VERSION 5.8 ;
BUSBITCHARS "[]" ;
DIVIDERCHAR "/" ;
UNITS
    DATABASE MICRONS 1000 ;
END UNITS

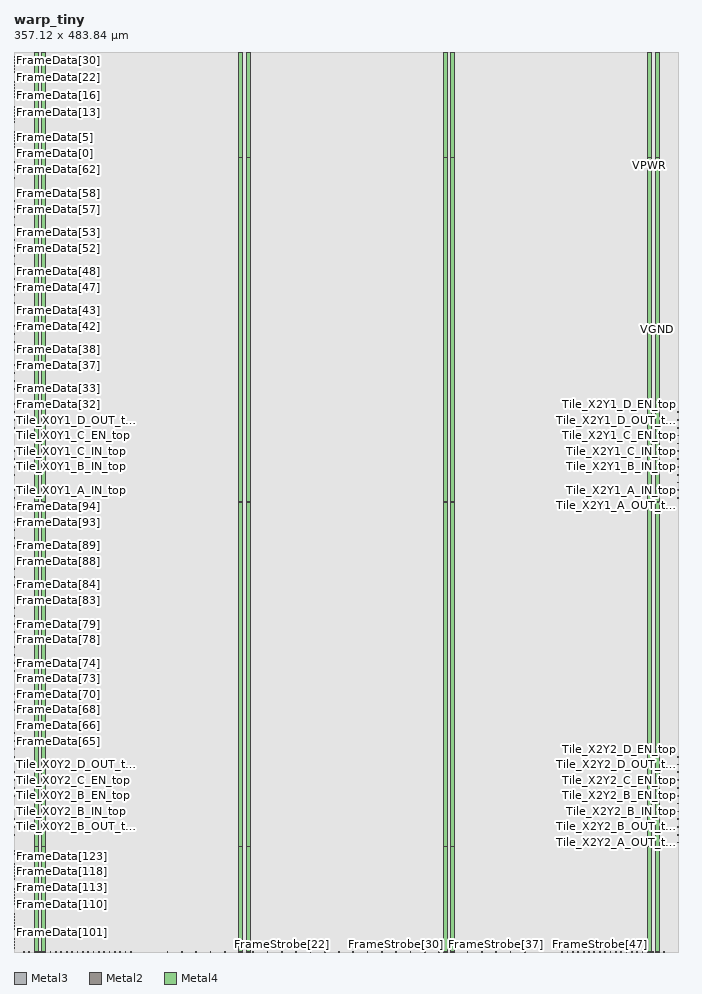
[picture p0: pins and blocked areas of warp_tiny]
MACRO warp_tiny
  FOREIGN warp_tiny 0 0 ;
  CLASS BLOCK ;
  SIZE 357.12 BY 483.84 ;
  PIN FrameData[0]
    DIRECTION INPUT ;
    USE SIGNAL ;
    PORT
      LAYER Metal3 ;
        RECT  0 429.04 0.4 429.44 ;
    END
  END FrameData[0]
  PIN FrameData[100]
    DIRECTION INPUT ;
    USE SIGNAL ;
    PORT
      LAYER Metal3 ;
        RECT  0 8.62 0.4 9.02 ;
    END
  END FrameData[100]
  PIN FrameData[101]
    DIRECTION INPUT ;
    USE SIGNAL ;
    PORT
      LAYER Metal3 ;
        RECT  0 10.3 0.4 10.7 ;
    END
  END FrameData[101]
  PIN FrameData[102]
    DIRECTION INPUT ;
    USE SIGNAL ;
    PORT
      LAYER Metal3 ;
        RECT  0 11.98 0.4 12.38 ;
    END
  END FrameData[102]
  PIN FrameData[103]
    DIRECTION INPUT ;
    USE SIGNAL ;
    PORT
      LAYER Metal3 ;
        RECT  0 13.66 0.4 14.06 ;
    END
  END FrameData[103]
  PIN FrameData[104]
    DIRECTION INPUT ;
    USE SIGNAL ;
    PORT
      LAYER Metal3 ;
        RECT  0 15.34 0.4 15.74 ;
    END
  END FrameData[104]
  PIN FrameData[105]
    DIRECTION INPUT ;
    USE SIGNAL ;
    PORT
      LAYER Metal3 ;
        RECT  0 17.02 0.4 17.42 ;
    END
  END FrameData[105]
  PIN FrameData[106]
    DIRECTION INPUT ;
    USE SIGNAL ;
    PORT
      LAYER Metal3 ;
        RECT  0 18.7 0.4 19.1 ;
    END
  END FrameData[106]
  PIN FrameData[107]
    DIRECTION INPUT ;
    USE SIGNAL ;
    PORT
      LAYER Metal3 ;
        RECT  0 20.38 0.4 20.78 ;
    END
  END FrameData[107]
  PIN FrameData[108]
    DIRECTION INPUT ;
    USE SIGNAL ;
    PORT
      LAYER Metal3 ;
        RECT  0 22.06 0.4 22.46 ;
    END
  END FrameData[108]
  PIN FrameData[109]
    DIRECTION INPUT ;
    USE SIGNAL ;
    PORT
      LAYER Metal3 ;
        RECT  0 23.74 0.4 24.14 ;
    END
  END FrameData[109]
  PIN FrameData[10]
    DIRECTION INPUT ;
    USE SIGNAL ;
    PORT
      LAYER Metal3 ;
        RECT  0 445.84 0.4 446.24 ;
    END
  END FrameData[10]
  PIN FrameData[110]
    DIRECTION INPUT ;
    USE SIGNAL ;
    PORT
      LAYER Metal3 ;
        RECT  0 25.42 0.4 25.82 ;
    END
  END FrameData[110]
  PIN FrameData[111]
    DIRECTION INPUT ;
    USE SIGNAL ;
    PORT
      LAYER Metal3 ;
        RECT  0 27.1 0.4 27.5 ;
    END
  END FrameData[111]
  PIN FrameData[112]
    DIRECTION INPUT ;
    USE SIGNAL ;
    PORT
      LAYER Metal3 ;
        RECT  0 28.78 0.4 29.18 ;
    END
  END FrameData[112]
  PIN FrameData[113]
    DIRECTION INPUT ;
    USE SIGNAL ;
    PORT
      LAYER Metal3 ;
        RECT  0 30.46 0.4 30.86 ;
    END
  END FrameData[113]
  PIN FrameData[114]
    DIRECTION INPUT ;
    USE SIGNAL ;
    PORT
      LAYER Metal3 ;
        RECT  0 32.14 0.4 32.54 ;
    END
  END FrameData[114]
  PIN FrameData[115]
    DIRECTION INPUT ;
    USE SIGNAL ;
    PORT
      LAYER Metal3 ;
        RECT  0 33.82 0.4 34.22 ;
    END
  END FrameData[115]
  PIN FrameData[116]
    DIRECTION INPUT ;
    USE SIGNAL ;
    PORT
      LAYER Metal3 ;
        RECT  0 35.5 0.4 35.9 ;
    END
  END FrameData[116]
  PIN FrameData[117]
    DIRECTION INPUT ;
    USE SIGNAL ;
    PORT
      LAYER Metal3 ;
        RECT  0 37.18 0.4 37.58 ;
    END
  END FrameData[117]
  PIN FrameData[118]
    DIRECTION INPUT ;
    USE SIGNAL ;
    PORT
      LAYER Metal3 ;
        RECT  0 38.86 0.4 39.26 ;
    END
  END FrameData[118]
  PIN FrameData[119]
    DIRECTION INPUT ;
    USE SIGNAL ;
    PORT
      LAYER Metal3 ;
        RECT  0 40.54 0.4 40.94 ;
    END
  END FrameData[119]
  PIN FrameData[11]
    DIRECTION INPUT ;
    USE SIGNAL ;
    PORT
      LAYER Metal3 ;
        RECT  0 447.52 0.4 447.92 ;
    END
  END FrameData[11]
  PIN FrameData[120]
    DIRECTION INPUT ;
    USE SIGNAL ;
    PORT
      LAYER Metal3 ;
        RECT  0 42.22 0.4 42.62 ;
    END
  END FrameData[120]
  PIN FrameData[121]
    DIRECTION INPUT ;
    USE SIGNAL ;
    PORT
      LAYER Metal3 ;
        RECT  0 43.9 0.4 44.3 ;
    END
  END FrameData[121]
  PIN FrameData[122]
    DIRECTION INPUT ;
    USE SIGNAL ;
    PORT
      LAYER Metal3 ;
        RECT  0 45.58 0.4 45.98 ;
    END
  END FrameData[122]
  PIN FrameData[123]
    DIRECTION INPUT ;
    USE SIGNAL ;
    PORT
      LAYER Metal3 ;
        RECT  0 47.26 0.4 47.66 ;
    END
  END FrameData[123]
  PIN FrameData[124]
    DIRECTION INPUT ;
    USE SIGNAL ;
    PORT
      LAYER Metal3 ;
        RECT  0 48.94 0.4 49.34 ;
    END
  END FrameData[124]
  PIN FrameData[125]
    DIRECTION INPUT ;
    USE SIGNAL ;
    PORT
      LAYER Metal3 ;
        RECT  0 50.62 0.4 51.02 ;
    END
  END FrameData[125]
  PIN FrameData[126]
    DIRECTION INPUT ;
    USE SIGNAL ;
    PORT
      LAYER Metal3 ;
        RECT  0 52.3 0.4 52.7 ;
    END
  END FrameData[126]
  PIN FrameData[127]
    DIRECTION INPUT ;
    USE SIGNAL ;
    PORT
      LAYER Metal3 ;
        RECT  0 53.98 0.4 54.38 ;
    END
  END FrameData[127]
  PIN FrameData[12]
    DIRECTION INPUT ;
    USE SIGNAL ;
    PORT
      LAYER Metal3 ;
        RECT  0 449.2 0.4 449.6 ;
    END
  END FrameData[12]
  PIN FrameData[13]
    DIRECTION INPUT ;
    USE SIGNAL ;
    PORT
      LAYER Metal3 ;
        RECT  0 450.88 0.4 451.28 ;
    END
  END FrameData[13]
  PIN FrameData[14]
    DIRECTION INPUT ;
    USE SIGNAL ;
    PORT
      LAYER Metal3 ;
        RECT  0 452.56 0.4 452.96 ;
    END
  END FrameData[14]
  PIN FrameData[15]
    DIRECTION INPUT ;
    USE SIGNAL ;
    PORT
      LAYER Metal3 ;
        RECT  0 454.24 0.4 454.64 ;
    END
  END FrameData[15]
  PIN FrameData[16]
    DIRECTION INPUT ;
    USE SIGNAL ;
    PORT
      LAYER Metal3 ;
        RECT  0 455.92 0.4 456.32 ;
    END
  END FrameData[16]
  PIN FrameData[17]
    DIRECTION INPUT ;
    USE SIGNAL ;
    PORT
      LAYER Metal3 ;
        RECT  0 457.6 0.4 458 ;
    END
  END FrameData[17]
  PIN FrameData[18]
    DIRECTION INPUT ;
    USE SIGNAL ;
    PORT
      LAYER Metal3 ;
        RECT  0 459.28 0.4 459.68 ;
    END
  END FrameData[18]
  PIN FrameData[19]
    DIRECTION INPUT ;
    USE SIGNAL ;
    PORT
      LAYER Metal3 ;
        RECT  0 460.96 0.4 461.36 ;
    END
  END FrameData[19]
  PIN FrameData[1]
    DIRECTION INPUT ;
    USE SIGNAL ;
    PORT
      LAYER Metal3 ;
        RECT  0 430.72 0.4 431.12 ;
    END
  END FrameData[1]
  PIN FrameData[20]
    DIRECTION INPUT ;
    USE SIGNAL ;
    PORT
      LAYER Metal3 ;
        RECT  0 462.64 0.4 463.04 ;
    END
  END FrameData[20]
  PIN FrameData[21]
    DIRECTION INPUT ;
    USE SIGNAL ;
    PORT
      LAYER Metal3 ;
        RECT  0 464.32 0.4 464.72 ;
    END
  END FrameData[21]
  PIN FrameData[22]
    DIRECTION INPUT ;
    USE SIGNAL ;
    PORT
      LAYER Metal3 ;
        RECT  0 466 0.4 466.4 ;
    END
  END FrameData[22]
  PIN FrameData[23]
    DIRECTION INPUT ;
    USE SIGNAL ;
    PORT
      LAYER Metal3 ;
        RECT  0 467.68 0.4 468.08 ;
    END
  END FrameData[23]
  PIN FrameData[24]
    DIRECTION INPUT ;
    USE SIGNAL ;
    PORT
      LAYER Metal3 ;
        RECT  0 469.36 0.4 469.76 ;
    END
  END FrameData[24]
  PIN FrameData[25]
    DIRECTION INPUT ;
    USE SIGNAL ;
    PORT
      LAYER Metal3 ;
        RECT  0 471.04 0.4 471.44 ;
    END
  END FrameData[25]
  PIN FrameData[26]
    DIRECTION INPUT ;
    USE SIGNAL ;
    PORT
      LAYER Metal3 ;
        RECT  0 472.72 0.4 473.12 ;
    END
  END FrameData[26]
  PIN FrameData[27]
    DIRECTION INPUT ;
    USE SIGNAL ;
    PORT
      LAYER Metal3 ;
        RECT  0 474.4 0.4 474.8 ;
    END
  END FrameData[27]
  PIN FrameData[28]
    DIRECTION INPUT ;
    USE SIGNAL ;
    PORT
      LAYER Metal3 ;
        RECT  0 476.08 0.4 476.48 ;
    END
  END FrameData[28]
  PIN FrameData[29]
    DIRECTION INPUT ;
    USE SIGNAL ;
    PORT
      LAYER Metal3 ;
        RECT  0 477.76 0.4 478.16 ;
    END
  END FrameData[29]
  PIN FrameData[2]
    DIRECTION INPUT ;
    USE SIGNAL ;
    PORT
      LAYER Metal3 ;
        RECT  0 432.4 0.4 432.8 ;
    END
  END FrameData[2]
  PIN FrameData[30]
    DIRECTION INPUT ;
    USE SIGNAL ;
    PORT
      LAYER Metal3 ;
        RECT  0 479.44 0.4 479.84 ;
    END
  END FrameData[30]
  PIN FrameData[31]
    DIRECTION INPUT ;
    USE SIGNAL ;
    PORT
      LAYER Metal3 ;
        RECT  0 481.12 0.4 481.52 ;
    END
  END FrameData[31]
  PIN FrameData[32]
    DIRECTION INPUT ;
    USE SIGNAL ;
    PORT
      LAYER Metal3 ;
        RECT  0 294.22 0.4 294.62 ;
    END
  END FrameData[32]
  PIN FrameData[33]
    DIRECTION INPUT ;
    USE SIGNAL ;
    PORT
      LAYER Metal3 ;
        RECT  0 298.42 0.4 298.82 ;
    END
  END FrameData[33]
  PIN FrameData[34]
    DIRECTION INPUT ;
    USE SIGNAL ;
    PORT
      LAYER Metal3 ;
        RECT  0 302.62 0.4 303.02 ;
    END
  END FrameData[34]
  PIN FrameData[35]
    DIRECTION INPUT ;
    USE SIGNAL ;
    PORT
      LAYER Metal3 ;
        RECT  0 306.82 0.4 307.22 ;
    END
  END FrameData[35]
  PIN FrameData[36]
    DIRECTION INPUT ;
    USE SIGNAL ;
    PORT
      LAYER Metal3 ;
        RECT  0 311.02 0.4 311.42 ;
    END
  END FrameData[36]
  PIN FrameData[37]
    DIRECTION INPUT ;
    USE SIGNAL ;
    PORT
      LAYER Metal3 ;
        RECT  0 315.22 0.4 315.62 ;
    END
  END FrameData[37]
  PIN FrameData[38]
    DIRECTION INPUT ;
    USE SIGNAL ;
    PORT
      LAYER Metal3 ;
        RECT  0 319.42 0.4 319.82 ;
    END
  END FrameData[38]
  PIN FrameData[39]
    DIRECTION INPUT ;
    USE SIGNAL ;
    PORT
      LAYER Metal3 ;
        RECT  0 323.62 0.4 324.02 ;
    END
  END FrameData[39]
  PIN FrameData[3]
    DIRECTION INPUT ;
    USE SIGNAL ;
    PORT
      LAYER Metal3 ;
        RECT  0 434.08 0.4 434.48 ;
    END
  END FrameData[3]
  PIN FrameData[40]
    DIRECTION INPUT ;
    USE SIGNAL ;
    PORT
      LAYER Metal3 ;
        RECT  0 327.82 0.4 328.22 ;
    END
  END FrameData[40]
  PIN FrameData[41]
    DIRECTION INPUT ;
    USE SIGNAL ;
    PORT
      LAYER Metal3 ;
        RECT  0 332.02 0.4 332.42 ;
    END
  END FrameData[41]
  PIN FrameData[42]
    DIRECTION INPUT ;
    USE SIGNAL ;
    PORT
      LAYER Metal3 ;
        RECT  0 336.22 0.4 336.62 ;
    END
  END FrameData[42]
  PIN FrameData[43]
    DIRECTION INPUT ;
    USE SIGNAL ;
    PORT
      LAYER Metal3 ;
        RECT  0 340.42 0.4 340.82 ;
    END
  END FrameData[43]
  PIN FrameData[44]
    DIRECTION INPUT ;
    USE SIGNAL ;
    PORT
      LAYER Metal3 ;
        RECT  0 344.62 0.4 345.02 ;
    END
  END FrameData[44]
  PIN FrameData[45]
    DIRECTION INPUT ;
    USE SIGNAL ;
    PORT
      LAYER Metal3 ;
        RECT  0 348.82 0.4 349.22 ;
    END
  END FrameData[45]
  PIN FrameData[46]
    DIRECTION INPUT ;
    USE SIGNAL ;
    PORT
      LAYER Metal3 ;
        RECT  0 353.02 0.4 353.42 ;
    END
  END FrameData[46]
  PIN FrameData[47]
    DIRECTION INPUT ;
    USE SIGNAL ;
    PORT
      LAYER Metal3 ;
        RECT  0 357.22 0.4 357.62 ;
    END
  END FrameData[47]
  PIN FrameData[48]
    DIRECTION INPUT ;
    USE SIGNAL ;
    PORT
      LAYER Metal3 ;
        RECT  0 361.42 0.4 361.82 ;
    END
  END FrameData[48]
  PIN FrameData[49]
    DIRECTION INPUT ;
    USE SIGNAL ;
    PORT
      LAYER Metal3 ;
        RECT  0 365.62 0.4 366.02 ;
    END
  END FrameData[49]
  PIN FrameData[4]
    DIRECTION INPUT ;
    USE SIGNAL ;
    PORT
      LAYER Metal3 ;
        RECT  0 435.76 0.4 436.16 ;
    END
  END FrameData[4]
  PIN FrameData[50]
    DIRECTION INPUT ;
    USE SIGNAL ;
    PORT
      LAYER Metal3 ;
        RECT  0 369.82 0.4 370.22 ;
    END
  END FrameData[50]
  PIN FrameData[51]
    DIRECTION INPUT ;
    USE SIGNAL ;
    PORT
      LAYER Metal3 ;
        RECT  0 374.02 0.4 374.42 ;
    END
  END FrameData[51]
  PIN FrameData[52]
    DIRECTION INPUT ;
    USE SIGNAL ;
    PORT
      LAYER Metal3 ;
        RECT  0 378.22 0.4 378.62 ;
    END
  END FrameData[52]
  PIN FrameData[53]
    DIRECTION INPUT ;
    USE SIGNAL ;
    PORT
      LAYER Metal3 ;
        RECT  0 382.42 0.4 382.82 ;
    END
  END FrameData[53]
  PIN FrameData[54]
    DIRECTION INPUT ;
    USE SIGNAL ;
    PORT
      LAYER Metal3 ;
        RECT  0 386.62 0.4 387.02 ;
    END
  END FrameData[54]
  PIN FrameData[55]
    DIRECTION INPUT ;
    USE SIGNAL ;
    PORT
      LAYER Metal3 ;
        RECT  0 390.82 0.4 391.22 ;
    END
  END FrameData[55]
  PIN FrameData[56]
    DIRECTION INPUT ;
    USE SIGNAL ;
    PORT
      LAYER Metal3 ;
        RECT  0 395.02 0.4 395.42 ;
    END
  END FrameData[56]
  PIN FrameData[57]
    DIRECTION INPUT ;
    USE SIGNAL ;
    PORT
      LAYER Metal3 ;
        RECT  0 399.22 0.4 399.62 ;
    END
  END FrameData[57]
  PIN FrameData[58]
    DIRECTION INPUT ;
    USE SIGNAL ;
    PORT
      LAYER Metal3 ;
        RECT  0 403.42 0.4 403.82 ;
    END
  END FrameData[58]
  PIN FrameData[59]
    DIRECTION INPUT ;
    USE SIGNAL ;
    PORT
      LAYER Metal3 ;
        RECT  0 407.62 0.4 408.02 ;
    END
  END FrameData[59]
  PIN FrameData[5]
    DIRECTION INPUT ;
    USE SIGNAL ;
    PORT
      LAYER Metal3 ;
        RECT  0 437.44 0.4 437.84 ;
    END
  END FrameData[5]
  PIN FrameData[60]
    DIRECTION INPUT ;
    USE SIGNAL ;
    PORT
      LAYER Metal3 ;
        RECT  0 411.82 0.4 412.22 ;
    END
  END FrameData[60]
  PIN FrameData[61]
    DIRECTION INPUT ;
    USE SIGNAL ;
    PORT
      LAYER Metal3 ;
        RECT  0 416.02 0.4 416.42 ;
    END
  END FrameData[61]
  PIN FrameData[62]
    DIRECTION INPUT ;
    USE SIGNAL ;
    PORT
      LAYER Metal3 ;
        RECT  0 420.22 0.4 420.62 ;
    END
  END FrameData[62]
  PIN FrameData[63]
    DIRECTION INPUT ;
    USE SIGNAL ;
    PORT
      LAYER Metal3 ;
        RECT  0 424.42 0.4 424.82 ;
    END
  END FrameData[63]
  PIN FrameData[64]
    DIRECTION INPUT ;
    USE SIGNAL ;
    PORT
      LAYER Metal3 ;
        RECT  0 109 0.4 109.4 ;
    END
  END FrameData[64]
  PIN FrameData[65]
    DIRECTION INPUT ;
    USE SIGNAL ;
    PORT
      LAYER Metal3 ;
        RECT  0 113.2 0.4 113.6 ;
    END
  END FrameData[65]
  PIN FrameData[66]
    DIRECTION INPUT ;
    USE SIGNAL ;
    PORT
      LAYER Metal3 ;
        RECT  0 117.4 0.4 117.8 ;
    END
  END FrameData[66]
  PIN FrameData[67]
    DIRECTION INPUT ;
    USE SIGNAL ;
    PORT
      LAYER Metal3 ;
        RECT  0 121.6 0.4 122 ;
    END
  END FrameData[67]
  PIN FrameData[68]
    DIRECTION INPUT ;
    USE SIGNAL ;
    PORT
      LAYER Metal3 ;
        RECT  0 125.8 0.4 126.2 ;
    END
  END FrameData[68]
  PIN FrameData[69]
    DIRECTION INPUT ;
    USE SIGNAL ;
    PORT
      LAYER Metal3 ;
        RECT  0 130 0.4 130.4 ;
    END
  END FrameData[69]
  PIN FrameData[6]
    DIRECTION INPUT ;
    USE SIGNAL ;
    PORT
      LAYER Metal3 ;
        RECT  0 439.12 0.4 439.52 ;
    END
  END FrameData[6]
  PIN FrameData[70]
    DIRECTION INPUT ;
    USE SIGNAL ;
    PORT
      LAYER Metal3 ;
        RECT  0 134.2 0.4 134.6 ;
    END
  END FrameData[70]
  PIN FrameData[71]
    DIRECTION INPUT ;
    USE SIGNAL ;
    PORT
      LAYER Metal3 ;
        RECT  0 138.4 0.4 138.8 ;
    END
  END FrameData[71]
  PIN FrameData[72]
    DIRECTION INPUT ;
    USE SIGNAL ;
    PORT
      LAYER Metal3 ;
        RECT  0 142.6 0.4 143 ;
    END
  END FrameData[72]
  PIN FrameData[73]
    DIRECTION INPUT ;
    USE SIGNAL ;
    PORT
      LAYER Metal3 ;
        RECT  0 146.8 0.4 147.2 ;
    END
  END FrameData[73]
  PIN FrameData[74]
    DIRECTION INPUT ;
    USE SIGNAL ;
    PORT
      LAYER Metal3 ;
        RECT  0 151 0.4 151.4 ;
    END
  END FrameData[74]
  PIN FrameData[75]
    DIRECTION INPUT ;
    USE SIGNAL ;
    PORT
      LAYER Metal3 ;
        RECT  0 155.2 0.4 155.6 ;
    END
  END FrameData[75]
  PIN FrameData[76]
    DIRECTION INPUT ;
    USE SIGNAL ;
    PORT
      LAYER Metal3 ;
        RECT  0 159.4 0.4 159.8 ;
    END
  END FrameData[76]
  PIN FrameData[77]
    DIRECTION INPUT ;
    USE SIGNAL ;
    PORT
      LAYER Metal3 ;
        RECT  0 163.6 0.4 164 ;
    END
  END FrameData[77]
  PIN FrameData[78]
    DIRECTION INPUT ;
    USE SIGNAL ;
    PORT
      LAYER Metal3 ;
        RECT  0 167.8 0.4 168.2 ;
    END
  END FrameData[78]
  PIN FrameData[79]
    DIRECTION INPUT ;
    USE SIGNAL ;
    PORT
      LAYER Metal3 ;
        RECT  0 172 0.4 172.4 ;
    END
  END FrameData[79]
  PIN FrameData[7]
    DIRECTION INPUT ;
    USE SIGNAL ;
    PORT
      LAYER Metal3 ;
        RECT  0 440.8 0.4 441.2 ;
    END
  END FrameData[7]
  PIN FrameData[80]
    DIRECTION INPUT ;
    USE SIGNAL ;
    PORT
      LAYER Metal3 ;
        RECT  0 176.2 0.4 176.6 ;
    END
  END FrameData[80]
  PIN FrameData[81]
    DIRECTION INPUT ;
    USE SIGNAL ;
    PORT
      LAYER Metal3 ;
        RECT  0 180.4 0.4 180.8 ;
    END
  END FrameData[81]
  PIN FrameData[82]
    DIRECTION INPUT ;
    USE SIGNAL ;
    PORT
      LAYER Metal3 ;
        RECT  0 184.6 0.4 185 ;
    END
  END FrameData[82]
  PIN FrameData[83]
    DIRECTION INPUT ;
    USE SIGNAL ;
    PORT
      LAYER Metal3 ;
        RECT  0 188.8 0.4 189.2 ;
    END
  END FrameData[83]
  PIN FrameData[84]
    DIRECTION INPUT ;
    USE SIGNAL ;
    PORT
      LAYER Metal3 ;
        RECT  0 193 0.4 193.4 ;
    END
  END FrameData[84]
  PIN FrameData[85]
    DIRECTION INPUT ;
    USE SIGNAL ;
    PORT
      LAYER Metal3 ;
        RECT  0 197.2 0.4 197.6 ;
    END
  END FrameData[85]
  PIN FrameData[86]
    DIRECTION INPUT ;
    USE SIGNAL ;
    PORT
      LAYER Metal3 ;
        RECT  0 201.4 0.4 201.8 ;
    END
  END FrameData[86]
  PIN FrameData[87]
    DIRECTION INPUT ;
    USE SIGNAL ;
    PORT
      LAYER Metal3 ;
        RECT  0 205.6 0.4 206 ;
    END
  END FrameData[87]
  PIN FrameData[88]
    DIRECTION INPUT ;
    USE SIGNAL ;
    PORT
      LAYER Metal3 ;
        RECT  0 209.8 0.4 210.2 ;
    END
  END FrameData[88]
  PIN FrameData[89]
    DIRECTION INPUT ;
    USE SIGNAL ;
    PORT
      LAYER Metal3 ;
        RECT  0 214 0.4 214.4 ;
    END
  END FrameData[89]
  PIN FrameData[8]
    DIRECTION INPUT ;
    USE SIGNAL ;
    PORT
      LAYER Metal3 ;
        RECT  0 442.48 0.4 442.88 ;
    END
  END FrameData[8]
  PIN FrameData[90]
    DIRECTION INPUT ;
    USE SIGNAL ;
    PORT
      LAYER Metal3 ;
        RECT  0 218.2 0.4 218.6 ;
    END
  END FrameData[90]
  PIN FrameData[91]
    DIRECTION INPUT ;
    USE SIGNAL ;
    PORT
      LAYER Metal3 ;
        RECT  0 222.4 0.4 222.8 ;
    END
  END FrameData[91]
  PIN FrameData[92]
    DIRECTION INPUT ;
    USE SIGNAL ;
    PORT
      LAYER Metal3 ;
        RECT  0 226.6 0.4 227 ;
    END
  END FrameData[92]
  PIN FrameData[93]
    DIRECTION INPUT ;
    USE SIGNAL ;
    PORT
      LAYER Metal3 ;
        RECT  0 230.8 0.4 231.2 ;
    END
  END FrameData[93]
  PIN FrameData[94]
    DIRECTION INPUT ;
    USE SIGNAL ;
    PORT
      LAYER Metal3 ;
        RECT  0 235 0.4 235.4 ;
    END
  END FrameData[94]
  PIN FrameData[95]
    DIRECTION INPUT ;
    USE SIGNAL ;
    PORT
      LAYER Metal3 ;
        RECT  0 239.2 0.4 239.6 ;
    END
  END FrameData[95]
  PIN FrameData[96]
    DIRECTION INPUT ;
    USE SIGNAL ;
    PORT
      LAYER Metal3 ;
        RECT  0 1.9 0.4 2.3 ;
    END
  END FrameData[96]
  PIN FrameData[97]
    DIRECTION INPUT ;
    USE SIGNAL ;
    PORT
      LAYER Metal3 ;
        RECT  0 3.58 0.4 3.98 ;
    END
  END FrameData[97]
  PIN FrameData[98]
    DIRECTION INPUT ;
    USE SIGNAL ;
    PORT
      LAYER Metal3 ;
        RECT  0 5.26 0.4 5.66 ;
    END
  END FrameData[98]
  PIN FrameData[99]
    DIRECTION INPUT ;
    USE SIGNAL ;
    PORT
      LAYER Metal3 ;
        RECT  0 6.94 0.4 7.34 ;
    END
  END FrameData[99]
  PIN FrameData[9]
    DIRECTION INPUT ;
    USE SIGNAL ;
    PORT
      LAYER Metal3 ;
        RECT  0 444.16 0.4 444.56 ;
    END
  END FrameData[9]
  PIN FrameStrobe[0]
    DIRECTION INPUT ;
    USE SIGNAL ;
    PORT
      LAYER Metal2 ;
        RECT  7.96 0 8.36 0.4 ;
    END
  END FrameStrobe[0]
  PIN FrameStrobe[10]
    DIRECTION INPUT ;
    USE SIGNAL ;
    PORT
      LAYER Metal2 ;
        RECT  36.76 0 37.16 0.4 ;
    END
  END FrameStrobe[10]
  PIN FrameStrobe[11]
    DIRECTION INPUT ;
    USE SIGNAL ;
    PORT
      LAYER Metal2 ;
        RECT  39.64 0 40.04 0.4 ;
    END
  END FrameStrobe[11]
  PIN FrameStrobe[12]
    DIRECTION INPUT ;
    USE SIGNAL ;
    PORT
      LAYER Metal2 ;
        RECT  42.52 0 42.92 0.4 ;
    END
  END FrameStrobe[12]
  PIN FrameStrobe[13]
    DIRECTION INPUT ;
    USE SIGNAL ;
    PORT
      LAYER Metal2 ;
        RECT  45.4 0 45.8 0.4 ;
    END
  END FrameStrobe[13]
  PIN FrameStrobe[14]
    DIRECTION INPUT ;
    USE SIGNAL ;
    PORT
      LAYER Metal2 ;
        RECT  48.28 0 48.68 0.4 ;
    END
  END FrameStrobe[14]
  PIN FrameStrobe[15]
    DIRECTION INPUT ;
    USE SIGNAL ;
    PORT
      LAYER Metal2 ;
        RECT  51.16 0 51.56 0.4 ;
    END
  END FrameStrobe[15]
  PIN FrameStrobe[16]
    DIRECTION INPUT ;
    USE SIGNAL ;
    PORT
      LAYER Metal2 ;
        RECT  54.04 0 54.44 0.4 ;
    END
  END FrameStrobe[16]
  PIN FrameStrobe[17]
    DIRECTION INPUT ;
    USE SIGNAL ;
    PORT
      LAYER Metal2 ;
        RECT  56.92 0 57.32 0.4 ;
    END
  END FrameStrobe[17]
  PIN FrameStrobe[18]
    DIRECTION INPUT ;
    USE SIGNAL ;
    PORT
      LAYER Metal2 ;
        RECT  59.8 0 60.2 0.4 ;
    END
  END FrameStrobe[18]
  PIN FrameStrobe[19]
    DIRECTION INPUT ;
    USE SIGNAL ;
    PORT
      LAYER Metal2 ;
        RECT  62.68 0 63.08 0.4 ;
    END
  END FrameStrobe[19]
  PIN FrameStrobe[1]
    DIRECTION INPUT ;
    USE SIGNAL ;
    PORT
      LAYER Metal2 ;
        RECT  10.84 0 11.24 0.4 ;
    END
  END FrameStrobe[1]
  PIN FrameStrobe[20]
    DIRECTION INPUT ;
    USE SIGNAL ;
    PORT
      LAYER Metal2 ;
        RECT  128.44 0 128.84 0.4 ;
    END
  END FrameStrobe[20]
  PIN FrameStrobe[21]
    DIRECTION INPUT ;
    USE SIGNAL ;
    PORT
      LAYER Metal2 ;
        RECT  136.12 0 136.52 0.4 ;
    END
  END FrameStrobe[21]
  PIN FrameStrobe[22]
    DIRECTION INPUT ;
    USE SIGNAL ;
    PORT
      LAYER Metal2 ;
        RECT  143.8 0 144.2 0.4 ;
    END
  END FrameStrobe[22]
  PIN FrameStrobe[23]
    DIRECTION INPUT ;
    USE SIGNAL ;
    PORT
      LAYER Metal2 ;
        RECT  151.48 0 151.88 0.4 ;
    END
  END FrameStrobe[23]
  PIN FrameStrobe[24]
    DIRECTION INPUT ;
    USE SIGNAL ;
    PORT
      LAYER Metal2 ;
        RECT  159.16 0 159.56 0.4 ;
    END
  END FrameStrobe[24]
  PIN FrameStrobe[25]
    DIRECTION INPUT ;
    USE SIGNAL ;
    PORT
      LAYER Metal2 ;
        RECT  166.84 0 167.24 0.4 ;
    END
  END FrameStrobe[25]
  PIN FrameStrobe[26]
    DIRECTION INPUT ;
    USE SIGNAL ;
    PORT
      LAYER Metal2 ;
        RECT  174.52 0 174.92 0.4 ;
    END
  END FrameStrobe[26]
  PIN FrameStrobe[27]
    DIRECTION INPUT ;
    USE SIGNAL ;
    PORT
      LAYER Metal2 ;
        RECT  182.2 0 182.6 0.4 ;
    END
  END FrameStrobe[27]
  PIN FrameStrobe[28]
    DIRECTION INPUT ;
    USE SIGNAL ;
    PORT
      LAYER Metal2 ;
        RECT  189.88 0 190.28 0.4 ;
    END
  END FrameStrobe[28]
  PIN FrameStrobe[29]
    DIRECTION INPUT ;
    USE SIGNAL ;
    PORT
      LAYER Metal2 ;
        RECT  197.56 0 197.96 0.4 ;
    END
  END FrameStrobe[29]
  PIN FrameStrobe[2]
    DIRECTION INPUT ;
    USE SIGNAL ;
    PORT
      LAYER Metal2 ;
        RECT  13.72 0 14.12 0.4 ;
    END
  END FrameStrobe[2]
  PIN FrameStrobe[30]
    DIRECTION INPUT ;
    USE SIGNAL ;
    PORT
      LAYER Metal2 ;
        RECT  205.24 0 205.64 0.4 ;
    END
  END FrameStrobe[30]
  PIN FrameStrobe[31]
    DIRECTION INPUT ;
    USE SIGNAL ;
    PORT
      LAYER Metal2 ;
        RECT  212.92 0 213.32 0.4 ;
    END
  END FrameStrobe[31]
  PIN FrameStrobe[32]
    DIRECTION INPUT ;
    USE SIGNAL ;
    PORT
      LAYER Metal2 ;
        RECT  220.6 0 221 0.4 ;
    END
  END FrameStrobe[32]
  PIN FrameStrobe[33]
    DIRECTION INPUT ;
    USE SIGNAL ;
    PORT
      LAYER Metal2 ;
        RECT  228.28 0 228.68 0.4 ;
    END
  END FrameStrobe[33]
  PIN FrameStrobe[34]
    DIRECTION INPUT ;
    USE SIGNAL ;
    PORT
      LAYER Metal2 ;
        RECT  235.96 0 236.36 0.4 ;
    END
  END FrameStrobe[34]
  PIN FrameStrobe[35]
    DIRECTION INPUT ;
    USE SIGNAL ;
    PORT
      LAYER Metal2 ;
        RECT  243.64 0 244.04 0.4 ;
    END
  END FrameStrobe[35]
  PIN FrameStrobe[36]
    DIRECTION INPUT ;
    USE SIGNAL ;
    PORT
      LAYER Metal2 ;
        RECT  251.32 0 251.72 0.4 ;
    END
  END FrameStrobe[36]
  PIN FrameStrobe[37]
    DIRECTION INPUT ;
    USE SIGNAL ;
    PORT
      LAYER Metal2 ;
        RECT  259 0 259.4 0.4 ;
    END
  END FrameStrobe[37]
  PIN FrameStrobe[38]
    DIRECTION INPUT ;
    USE SIGNAL ;
    PORT
      LAYER Metal2 ;
        RECT  266.68 0 267.08 0.4 ;
    END
  END FrameStrobe[38]
  PIN FrameStrobe[39]
    DIRECTION INPUT ;
    USE SIGNAL ;
    PORT
      LAYER Metal2 ;
        RECT  274.36 0 274.76 0.4 ;
    END
  END FrameStrobe[39]
  PIN FrameStrobe[3]
    DIRECTION INPUT ;
    USE SIGNAL ;
    PORT
      LAYER Metal2 ;
        RECT  16.6 0 17 0.4 ;
    END
  END FrameStrobe[3]
  PIN FrameStrobe[40]
    DIRECTION INPUT ;
    USE SIGNAL ;
    PORT
      LAYER Metal2 ;
        RECT  294.52 0 294.92 0.4 ;
    END
  END FrameStrobe[40]
  PIN FrameStrobe[41]
    DIRECTION INPUT ;
    USE SIGNAL ;
    PORT
      LAYER Metal2 ;
        RECT  297.4 0 297.8 0.4 ;
    END
  END FrameStrobe[41]
  PIN FrameStrobe[42]
    DIRECTION INPUT ;
    USE SIGNAL ;
    PORT
      LAYER Metal2 ;
        RECT  300.28 0 300.68 0.4 ;
    END
  END FrameStrobe[42]
  PIN FrameStrobe[43]
    DIRECTION INPUT ;
    USE SIGNAL ;
    PORT
      LAYER Metal2 ;
        RECT  303.16 0 303.56 0.4 ;
    END
  END FrameStrobe[43]
  PIN FrameStrobe[44]
    DIRECTION INPUT ;
    USE SIGNAL ;
    PORT
      LAYER Metal2 ;
        RECT  306.04 0 306.44 0.4 ;
    END
  END FrameStrobe[44]
  PIN FrameStrobe[45]
    DIRECTION INPUT ;
    USE SIGNAL ;
    PORT
      LAYER Metal2 ;
        RECT  308.92 0 309.32 0.4 ;
    END
  END FrameStrobe[45]
  PIN FrameStrobe[46]
    DIRECTION INPUT ;
    USE SIGNAL ;
    PORT
      LAYER Metal2 ;
        RECT  311.8 0 312.2 0.4 ;
    END
  END FrameStrobe[46]
  PIN FrameStrobe[47]
    DIRECTION INPUT ;
    USE SIGNAL ;
    PORT
      LAYER Metal2 ;
        RECT  314.68 0 315.08 0.4 ;
    END
  END FrameStrobe[47]
  PIN FrameStrobe[48]
    DIRECTION INPUT ;
    USE SIGNAL ;
    PORT
      LAYER Metal2 ;
        RECT  317.56 0 317.96 0.4 ;
    END
  END FrameStrobe[48]
  PIN FrameStrobe[49]
    DIRECTION INPUT ;
    USE SIGNAL ;
    PORT
      LAYER Metal2 ;
        RECT  320.44 0 320.84 0.4 ;
    END
  END FrameStrobe[49]
  PIN FrameStrobe[4]
    DIRECTION INPUT ;
    USE SIGNAL ;
    PORT
      LAYER Metal2 ;
        RECT  19.48 0 19.88 0.4 ;
    END
  END FrameStrobe[4]
  PIN FrameStrobe[50]
    DIRECTION INPUT ;
    USE SIGNAL ;
    PORT
      LAYER Metal2 ;
        RECT  323.32 0 323.72 0.4 ;
    END
  END FrameStrobe[50]
  PIN FrameStrobe[51]
    DIRECTION INPUT ;
    USE SIGNAL ;
    PORT
      LAYER Metal2 ;
        RECT  326.2 0 326.6 0.4 ;
    END
  END FrameStrobe[51]
  PIN FrameStrobe[52]
    DIRECTION INPUT ;
    USE SIGNAL ;
    PORT
      LAYER Metal2 ;
        RECT  329.08 0 329.48 0.4 ;
    END
  END FrameStrobe[52]
  PIN FrameStrobe[53]
    DIRECTION INPUT ;
    USE SIGNAL ;
    PORT
      LAYER Metal2 ;
        RECT  331.96 0 332.36 0.4 ;
    END
  END FrameStrobe[53]
  PIN FrameStrobe[54]
    DIRECTION INPUT ;
    USE SIGNAL ;
    PORT
      LAYER Metal2 ;
        RECT  334.84 0 335.24 0.4 ;
    END
  END FrameStrobe[54]
  PIN FrameStrobe[55]
    DIRECTION INPUT ;
    USE SIGNAL ;
    PORT
      LAYER Metal2 ;
        RECT  337.72 0 338.12 0.4 ;
    END
  END FrameStrobe[55]
  PIN FrameStrobe[56]
    DIRECTION INPUT ;
    USE SIGNAL ;
    PORT
      LAYER Metal2 ;
        RECT  340.6 0 341 0.4 ;
    END
  END FrameStrobe[56]
  PIN FrameStrobe[57]
    DIRECTION INPUT ;
    USE SIGNAL ;
    PORT
      LAYER Metal2 ;
        RECT  343.48 0 343.88 0.4 ;
    END
  END FrameStrobe[57]
  PIN FrameStrobe[58]
    DIRECTION INPUT ;
    USE SIGNAL ;
    PORT
      LAYER Metal2 ;
        RECT  346.36 0 346.76 0.4 ;
    END
  END FrameStrobe[58]
  PIN FrameStrobe[59]
    DIRECTION INPUT ;
    USE SIGNAL ;
    PORT
      LAYER Metal2 ;
        RECT  349.24 0 349.64 0.4 ;
    END
  END FrameStrobe[59]
  PIN FrameStrobe[5]
    DIRECTION INPUT ;
    USE SIGNAL ;
    PORT
      LAYER Metal2 ;
        RECT  22.36 0 22.76 0.4 ;
    END
  END FrameStrobe[5]
  PIN FrameStrobe[6]
    DIRECTION INPUT ;
    USE SIGNAL ;
    PORT
      LAYER Metal2 ;
        RECT  25.24 0 25.64 0.4 ;
    END
  END FrameStrobe[6]
  PIN FrameStrobe[7]
    DIRECTION INPUT ;
    USE SIGNAL ;
    PORT
      LAYER Metal2 ;
        RECT  28.12 0 28.52 0.4 ;
    END
  END FrameStrobe[7]
  PIN FrameStrobe[8]
    DIRECTION INPUT ;
    USE SIGNAL ;
    PORT
      LAYER Metal2 ;
        RECT  31 0 31.4 0.4 ;
    END
  END FrameStrobe[8]
  PIN FrameStrobe[9]
    DIRECTION INPUT ;
    USE SIGNAL ;
    PORT
      LAYER Metal2 ;
        RECT  33.88 0 34.28 0.4 ;
    END
  END FrameStrobe[9]
  PIN Tile_X0Y1_A_EN_top
    DIRECTION OUTPUT ;
    USE SIGNAL ;
    PORT
      LAYER Metal3 ;
        RECT  0 252.22 0.4 252.62 ;
    END
  END Tile_X0Y1_A_EN_top
  PIN Tile_X0Y1_A_IN_top
    DIRECTION OUTPUT ;
    USE SIGNAL ;
    PORT
      LAYER Metal3 ;
        RECT  0 248.02 0.4 248.42 ;
    END
  END Tile_X0Y1_A_IN_top
  PIN Tile_X0Y1_A_OUT_top
    DIRECTION INPUT ;
    USE SIGNAL ;
    PORT
      LAYER Metal3 ;
        RECT  0 243.82 0.4 244.22 ;
    END
  END Tile_X0Y1_A_OUT_top
  PIN Tile_X0Y1_B_EN_top
    DIRECTION OUTPUT ;
    USE SIGNAL ;
    PORT
      LAYER Metal3 ;
        RECT  0 264.82 0.4 265.22 ;
    END
  END Tile_X0Y1_B_EN_top
  PIN Tile_X0Y1_B_IN_top
    DIRECTION OUTPUT ;
    USE SIGNAL ;
    PORT
      LAYER Metal3 ;
        RECT  0 260.62 0.4 261.02 ;
    END
  END Tile_X0Y1_B_IN_top
  PIN Tile_X0Y1_B_OUT_top
    DIRECTION INPUT ;
    USE SIGNAL ;
    PORT
      LAYER Metal3 ;
        RECT  0 256.42 0.4 256.82 ;
    END
  END Tile_X0Y1_B_OUT_top
  PIN Tile_X0Y1_C_EN_top
    DIRECTION OUTPUT ;
    USE SIGNAL ;
    PORT
      LAYER Metal3 ;
        RECT  0 277.42 0.4 277.82 ;
    END
  END Tile_X0Y1_C_EN_top
  PIN Tile_X0Y1_C_IN_top
    DIRECTION OUTPUT ;
    USE SIGNAL ;
    PORT
      LAYER Metal3 ;
        RECT  0 273.22 0.4 273.62 ;
    END
  END Tile_X0Y1_C_IN_top
  PIN Tile_X0Y1_C_OUT_top
    DIRECTION INPUT ;
    USE SIGNAL ;
    PORT
      LAYER Metal3 ;
        RECT  0 269.02 0.4 269.42 ;
    END
  END Tile_X0Y1_C_OUT_top
  PIN Tile_X0Y1_D_EN_top
    DIRECTION OUTPUT ;
    USE SIGNAL ;
    PORT
      LAYER Metal3 ;
        RECT  0 290.02 0.4 290.42 ;
    END
  END Tile_X0Y1_D_EN_top
  PIN Tile_X0Y1_D_IN_top
    DIRECTION OUTPUT ;
    USE SIGNAL ;
    PORT
      LAYER Metal3 ;
        RECT  0 285.82 0.4 286.22 ;
    END
  END Tile_X0Y1_D_IN_top
  PIN Tile_X0Y1_D_OUT_top
    DIRECTION INPUT ;
    USE SIGNAL ;
    PORT
      LAYER Metal3 ;
        RECT  0 281.62 0.4 282.02 ;
    END
  END Tile_X0Y1_D_OUT_top
  PIN Tile_X0Y2_A_EN_top
    DIRECTION OUTPUT ;
    USE SIGNAL ;
    PORT
      LAYER Metal3 ;
        RECT  0 67 0.4 67.4 ;
    END
  END Tile_X0Y2_A_EN_top
  PIN Tile_X0Y2_A_IN_top
    DIRECTION OUTPUT ;
    USE SIGNAL ;
    PORT
      LAYER Metal3 ;
        RECT  0 62.8 0.4 63.2 ;
    END
  END Tile_X0Y2_A_IN_top
  PIN Tile_X0Y2_A_OUT_top
    DIRECTION INPUT ;
    USE SIGNAL ;
    PORT
      LAYER Metal3 ;
        RECT  0 58.6 0.4 59 ;
    END
  END Tile_X0Y2_A_OUT_top
  PIN Tile_X0Y2_B_EN_top
    DIRECTION OUTPUT ;
    USE SIGNAL ;
    PORT
      LAYER Metal3 ;
        RECT  0 79.6 0.4 80 ;
    END
  END Tile_X0Y2_B_EN_top
  PIN Tile_X0Y2_B_IN_top
    DIRECTION OUTPUT ;
    USE SIGNAL ;
    PORT
      LAYER Metal3 ;
        RECT  0 75.4 0.4 75.8 ;
    END
  END Tile_X0Y2_B_IN_top
  PIN Tile_X0Y2_B_OUT_top
    DIRECTION INPUT ;
    USE SIGNAL ;
    PORT
      LAYER Metal3 ;
        RECT  0 71.2 0.4 71.6 ;
    END
  END Tile_X0Y2_B_OUT_top
  PIN Tile_X0Y2_C_EN_top
    DIRECTION OUTPUT ;
    USE SIGNAL ;
    PORT
      LAYER Metal3 ;
        RECT  0 92.2 0.4 92.6 ;
    END
  END Tile_X0Y2_C_EN_top
  PIN Tile_X0Y2_C_IN_top
    DIRECTION OUTPUT ;
    USE SIGNAL ;
    PORT
      LAYER Metal3 ;
        RECT  0 88 0.4 88.4 ;
    END
  END Tile_X0Y2_C_IN_top
  PIN Tile_X0Y2_C_OUT_top
    DIRECTION INPUT ;
    USE SIGNAL ;
    PORT
      LAYER Metal3 ;
        RECT  0 83.8 0.4 84.2 ;
    END
  END Tile_X0Y2_C_OUT_top
  PIN Tile_X0Y2_D_EN_top
    DIRECTION OUTPUT ;
    USE SIGNAL ;
    PORT
      LAYER Metal3 ;
        RECT  0 104.8 0.4 105.2 ;
    END
  END Tile_X0Y2_D_EN_top
  PIN Tile_X0Y2_D_IN_top
    DIRECTION OUTPUT ;
    USE SIGNAL ;
    PORT
      LAYER Metal3 ;
        RECT  0 100.6 0.4 101 ;
    END
  END Tile_X0Y2_D_IN_top
  PIN Tile_X0Y2_D_OUT_top
    DIRECTION INPUT ;
    USE SIGNAL ;
    PORT
      LAYER Metal3 ;
        RECT  0 96.4 0.4 96.8 ;
    END
  END Tile_X0Y2_D_OUT_top
  PIN Tile_X0Y3_SYS_RESET_RESET_top
    DIRECTION INPUT ;
    USE SIGNAL ;
    PORT
      LAYER Metal2 ;
        RECT  5.08 0 5.48 0.4 ;
    END
  END Tile_X0Y3_SYS_RESET_RESET_top
  PIN Tile_X1Y3_A_EN_top
    DIRECTION OUTPUT ;
    USE SIGNAL ;
    PORT
      LAYER Metal2 ;
        RECT  97.72 0 98.12 0.4 ;
    END
  END Tile_X1Y3_A_EN_top
  PIN Tile_X1Y3_A_IN_top
    DIRECTION OUTPUT ;
    USE SIGNAL ;
    PORT
      LAYER Metal2 ;
        RECT  90.04 0 90.44 0.4 ;
    END
  END Tile_X1Y3_A_IN_top
  PIN Tile_X1Y3_A_OUT_top
    DIRECTION INPUT ;
    USE SIGNAL ;
    PORT
      LAYER Metal2 ;
        RECT  82.36 0 82.76 0.4 ;
    END
  END Tile_X1Y3_A_OUT_top
  PIN Tile_X1Y3_B_EN_top
    DIRECTION OUTPUT ;
    USE SIGNAL ;
    PORT
      LAYER Metal2 ;
        RECT  120.76 0 121.16 0.4 ;
    END
  END Tile_X1Y3_B_EN_top
  PIN Tile_X1Y3_B_IN_top
    DIRECTION OUTPUT ;
    USE SIGNAL ;
    PORT
      LAYER Metal2 ;
        RECT  113.08 0 113.48 0.4 ;
    END
  END Tile_X1Y3_B_IN_top
  PIN Tile_X1Y3_B_OUT_top
    DIRECTION INPUT ;
    USE SIGNAL ;
    PORT
      LAYER Metal2 ;
        RECT  105.4 0 105.8 0.4 ;
    END
  END Tile_X1Y3_B_OUT_top
  PIN Tile_X2Y1_A_EN_top
    DIRECTION OUTPUT ;
    USE SIGNAL ;
    PORT
      LAYER Metal3 ;
        RECT  356.72 252.22 357.12 252.62 ;
    END
  END Tile_X2Y1_A_EN_top
  PIN Tile_X2Y1_A_IN_top
    DIRECTION OUTPUT ;
    USE SIGNAL ;
    PORT
      LAYER Metal3 ;
        RECT  356.72 248.02 357.12 248.42 ;
    END
  END Tile_X2Y1_A_IN_top
  PIN Tile_X2Y1_A_OUT_top
    DIRECTION INPUT ;
    USE SIGNAL ;
    PORT
      LAYER Metal3 ;
        RECT  356.72 243.82 357.12 244.22 ;
    END
  END Tile_X2Y1_A_OUT_top
  PIN Tile_X2Y1_B_EN_top
    DIRECTION OUTPUT ;
    USE SIGNAL ;
    PORT
      LAYER Metal3 ;
        RECT  356.72 264.82 357.12 265.22 ;
    END
  END Tile_X2Y1_B_EN_top
  PIN Tile_X2Y1_B_IN_top
    DIRECTION OUTPUT ;
    USE SIGNAL ;
    PORT
      LAYER Metal3 ;
        RECT  356.72 260.62 357.12 261.02 ;
    END
  END Tile_X2Y1_B_IN_top
  PIN Tile_X2Y1_B_OUT_top
    DIRECTION INPUT ;
    USE SIGNAL ;
    PORT
      LAYER Metal3 ;
        RECT  356.72 256.42 357.12 256.82 ;
    END
  END Tile_X2Y1_B_OUT_top
  PIN Tile_X2Y1_C_EN_top
    DIRECTION OUTPUT ;
    USE SIGNAL ;
    PORT
      LAYER Metal3 ;
        RECT  356.72 277.42 357.12 277.82 ;
    END
  END Tile_X2Y1_C_EN_top
  PIN Tile_X2Y1_C_IN_top
    DIRECTION OUTPUT ;
    USE SIGNAL ;
    PORT
      LAYER Metal3 ;
        RECT  356.72 273.22 357.12 273.62 ;
    END
  END Tile_X2Y1_C_IN_top
  PIN Tile_X2Y1_C_OUT_top
    DIRECTION INPUT ;
    USE SIGNAL ;
    PORT
      LAYER Metal3 ;
        RECT  356.72 269.02 357.12 269.42 ;
    END
  END Tile_X2Y1_C_OUT_top
  PIN Tile_X2Y1_D_EN_top
    DIRECTION OUTPUT ;
    USE SIGNAL ;
    PORT
      LAYER Metal3 ;
        RECT  356.72 290.02 357.12 290.42 ;
    END
  END Tile_X2Y1_D_EN_top
  PIN Tile_X2Y1_D_IN_top
    DIRECTION OUTPUT ;
    USE SIGNAL ;
    PORT
      LAYER Metal3 ;
        RECT  356.72 285.82 357.12 286.22 ;
    END
  END Tile_X2Y1_D_IN_top
  PIN Tile_X2Y1_D_OUT_top
    DIRECTION INPUT ;
    USE SIGNAL ;
    PORT
      LAYER Metal3 ;
        RECT  356.72 281.62 357.12 282.02 ;
    END
  END Tile_X2Y1_D_OUT_top
  PIN Tile_X2Y2_A_EN_top
    DIRECTION OUTPUT ;
    USE SIGNAL ;
    PORT
      LAYER Metal3 ;
        RECT  356.72 67 357.12 67.4 ;
    END
  END Tile_X2Y2_A_EN_top
  PIN Tile_X2Y2_A_IN_top
    DIRECTION OUTPUT ;
    USE SIGNAL ;
    PORT
      LAYER Metal3 ;
        RECT  356.72 62.8 357.12 63.2 ;
    END
  END Tile_X2Y2_A_IN_top
  PIN Tile_X2Y2_A_OUT_top
    DIRECTION INPUT ;
    USE SIGNAL ;
    PORT
      LAYER Metal3 ;
        RECT  356.72 58.6 357.12 59 ;
    END
  END Tile_X2Y2_A_OUT_top
  PIN Tile_X2Y2_B_EN_top
    DIRECTION OUTPUT ;
    USE SIGNAL ;
    PORT
      LAYER Metal3 ;
        RECT  356.72 79.6 357.12 80 ;
    END
  END Tile_X2Y2_B_EN_top
  PIN Tile_X2Y2_B_IN_top
    DIRECTION OUTPUT ;
    USE SIGNAL ;
    PORT
      LAYER Metal3 ;
        RECT  356.72 75.4 357.12 75.8 ;
    END
  END Tile_X2Y2_B_IN_top
  PIN Tile_X2Y2_B_OUT_top
    DIRECTION INPUT ;
    USE SIGNAL ;
    PORT
      LAYER Metal3 ;
        RECT  356.72 71.2 357.12 71.6 ;
    END
  END Tile_X2Y2_B_OUT_top
  PIN Tile_X2Y2_C_EN_top
    DIRECTION OUTPUT ;
    USE SIGNAL ;
    PORT
      LAYER Metal3 ;
        RECT  356.72 92.2 357.12 92.6 ;
    END
  END Tile_X2Y2_C_EN_top
  PIN Tile_X2Y2_C_IN_top
    DIRECTION OUTPUT ;
    USE SIGNAL ;
    PORT
      LAYER Metal3 ;
        RECT  356.72 88 357.12 88.4 ;
    END
  END Tile_X2Y2_C_IN_top
  PIN Tile_X2Y2_C_OUT_top
    DIRECTION INPUT ;
    USE SIGNAL ;
    PORT
      LAYER Metal3 ;
        RECT  356.72 83.8 357.12 84.2 ;
    END
  END Tile_X2Y2_C_OUT_top
  PIN Tile_X2Y2_D_EN_top
    DIRECTION OUTPUT ;
    USE SIGNAL ;
    PORT
      LAYER Metal3 ;
        RECT  356.72 104.8 357.12 105.2 ;
    END
  END Tile_X2Y2_D_EN_top
  PIN Tile_X2Y2_D_IN_top
    DIRECTION OUTPUT ;
    USE SIGNAL ;
    PORT
      LAYER Metal3 ;
        RECT  356.72 100.6 357.12 101 ;
    END
  END Tile_X2Y2_D_IN_top
  PIN Tile_X2Y2_D_OUT_top
    DIRECTION INPUT ;
    USE SIGNAL ;
    PORT
      LAYER Metal3 ;
        RECT  356.72 96.4 357.12 96.8 ;
    END
  END Tile_X2Y2_D_OUT_top
  PIN VPWR
    DIRECTION INOUT ;
    USE POWER ;
    PORT
      LAYER Metal4 ;
        RECT  340.71 0 342.81 56.7 ;
        RECT  340.71 0 342.81 0.2 ;
        RECT  340.71 56.5 342.81 56.7 ;
        RECT  340.71 56.7 342.81 241.92 ;
        RECT  340.71 56.7 342.81 56.9 ;
        RECT  340.71 241.72 342.81 241.92 ;
        RECT  340.71 241.92 342.81 427.14 ;
        RECT  340.71 241.92 342.81 242.12 ;
        RECT  340.71 426.94 342.81 427.14 ;
        RECT  340.71 427.14 342.81 483.84 ;
        RECT  340.71 427.14 342.81 427.34 ;
        RECT  340.71 483.64 342.81 483.84 ;
        RECT  120.87 0 122.97 56.7 ;
        RECT  120.87 0 122.97 0.2 ;
        RECT  120.87 56.5 122.97 56.7 ;
        RECT  230.79 0 232.89 56.7 ;
        RECT  230.79 0 232.89 0.2 ;
        RECT  230.79 56.5 232.89 56.7 ;
        RECT  120.87 56.7 122.97 241.92 ;
        RECT  120.87 56.7 122.97 56.9 ;
        RECT  120.87 241.72 122.97 241.92 ;
        RECT  230.79 56.7 232.89 241.92 ;
        RECT  230.79 56.7 232.89 56.9 ;
        RECT  230.79 241.72 232.89 241.92 ;
        RECT  120.87 241.92 122.97 427.14 ;
        RECT  120.87 241.92 122.97 242.12 ;
        RECT  120.87 426.94 122.97 427.14 ;
        RECT  230.79 241.92 232.89 427.14 ;
        RECT  230.79 241.92 232.89 242.12 ;
        RECT  230.79 426.94 232.89 427.14 ;
        RECT  120.87 427.14 122.97 483.84 ;
        RECT  120.87 427.14 122.97 427.34 ;
        RECT  120.87 483.64 122.97 483.84 ;
        RECT  230.79 427.14 232.89 483.84 ;
        RECT  230.79 427.14 232.89 427.34 ;
        RECT  230.79 483.64 232.89 483.84 ;
        RECT  10.95 0 13.05 56.7 ;
        RECT  10.95 0 13.05 0.2 ;
        RECT  10.95 56.5 13.05 56.7 ;
        RECT  10.95 56.7 13.05 241.92 ;
        RECT  10.95 56.7 13.05 56.9 ;
        RECT  10.95 241.72 13.05 241.92 ;
        RECT  10.95 241.92 13.05 427.14 ;
        RECT  10.95 241.92 13.05 242.12 ;
        RECT  10.95 426.94 13.05 427.14 ;
        RECT  10.95 427.14 13.05 483.84 ;
        RECT  10.95 427.14 13.05 427.34 ;
        RECT  10.95 483.64 13.05 483.84 ;
    END
  END VPWR
  PIN VGND
    DIRECTION INOUT ;
    USE GROUND ;
    PORT
      LAYER Metal4 ;
        RECT  344.81 0 346.91 56.7 ;
        RECT  344.81 0 346.91 0.2 ;
        RECT  344.81 56.5 346.91 56.7 ;
        RECT  344.81 56.7 346.91 241.92 ;
        RECT  344.81 56.7 346.91 56.9 ;
        RECT  344.81 241.72 346.91 241.92 ;
        RECT  344.81 241.92 346.91 427.14 ;
        RECT  344.81 241.92 346.91 242.12 ;
        RECT  344.81 426.94 346.91 427.14 ;
        RECT  344.81 427.14 346.91 483.84 ;
        RECT  344.81 427.14 346.91 427.34 ;
        RECT  344.81 483.64 346.91 483.84 ;
        RECT  124.97 0 127.07 56.7 ;
        RECT  124.97 0 127.07 0.2 ;
        RECT  124.97 56.5 127.07 56.7 ;
        RECT  234.89 0 236.99 56.7 ;
        RECT  234.89 0 236.99 0.2 ;
        RECT  234.89 56.5 236.99 56.7 ;
        RECT  124.97 56.7 127.07 241.92 ;
        RECT  124.97 56.7 127.07 56.9 ;
        RECT  124.97 241.72 127.07 241.92 ;
        RECT  234.89 56.7 236.99 241.92 ;
        RECT  234.89 56.7 236.99 56.9 ;
        RECT  234.89 241.72 236.99 241.92 ;
        RECT  124.97 241.92 127.07 427.14 ;
        RECT  124.97 241.92 127.07 242.12 ;
        RECT  124.97 426.94 127.07 427.14 ;
        RECT  234.89 241.92 236.99 427.14 ;
        RECT  234.89 241.92 236.99 242.12 ;
        RECT  234.89 426.94 236.99 427.14 ;
        RECT  124.97 427.14 127.07 483.84 ;
        RECT  124.97 427.14 127.07 427.34 ;
        RECT  124.97 483.64 127.07 483.84 ;
        RECT  234.89 427.14 236.99 483.84 ;
        RECT  234.89 427.14 236.99 427.34 ;
        RECT  234.89 483.64 236.99 483.84 ;
        RECT  15.05 0 17.15 56.7 ;
        RECT  15.05 0 17.15 0.2 ;
        RECT  15.05 56.5 17.15 56.7 ;
        RECT  15.05 56.7 17.15 241.92 ;
        RECT  15.05 56.7 17.15 56.9 ;
        RECT  15.05 241.72 17.15 241.92 ;
        RECT  15.05 241.92 17.15 427.14 ;
        RECT  15.05 241.92 17.15 242.12 ;
        RECT  15.05 426.94 17.15 427.14 ;
        RECT  15.05 427.14 17.15 483.84 ;
        RECT  15.05 427.14 17.15 427.34 ;
        RECT  15.05 483.64 17.15 483.84 ;
    END
  END VGND
  OBS
    LAYER Metal1 ;
     RECT  0 0 357.12 483.84 ;
    LAYER Metal2 ;
     RECT  0 0 357.12 483.84 ;
    LAYER Metal3 ;
     RECT  0 0 357.12 483.84 ;
    LAYER Metal4 ;
     RECT  0 0 357.12 483.84 ;
  END
END warp_tiny
END LIBRARY
